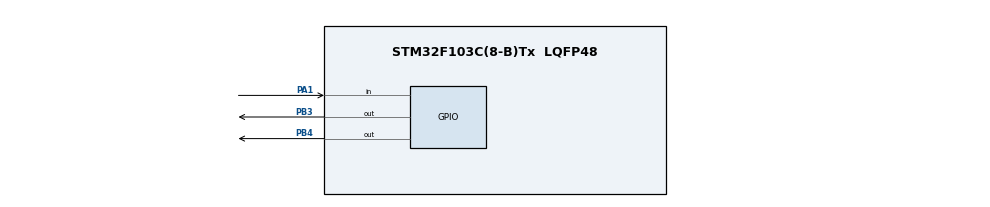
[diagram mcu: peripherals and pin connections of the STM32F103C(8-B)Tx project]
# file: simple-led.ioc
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Mcu.Family=STM32F1
Mcu.Name=STM32F103C(8-B)Tx
Mcu.Package=LQFP48
NVIC.PriorityGroup=NVIC_PRIORITYGROUP_4
PA1.Signal=GPIO_Input
PB3.Signal=GPIO_Output
PB4.Signal=GPIO_Output
ProjectManager.HeapSize=0x200
ProjectManager.StackSize=0x400
ProjectManager.TargetToolchain=STM32CubeIDE
RCC.APB1Freq_Value=8000000
RCC.APB2Freq_Value=8000000
VP_SYS_VS_ND.Mode=No_Debug
board=custom

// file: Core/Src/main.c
/* USER CODE BEGIN Header */
/**
  ******************************************************************************
  * @file           : main.c
  * @brief          : Main program body
  ******************************************************************************
  * @attention
  *
  * Copyright (c) 2023 STMicroelectronics.
  * All rights reserved.
  *
  * This software is licensed under terms that can be found in the LICENSE file
  * in the root directory of this software component.
  * If no LICENSE file comes with this software, it is provided AS-IS.
  *
  ******************************************************************************
  */
/* USER CODE END Header */
#include "main.h"
#include "led.h"
#include "key.h"

LED_TOGGLE(5, GPIOB, GPIO_PIN_5)

LED_TOGGLE(6, GPIOB, GPIO_PIN_6)

void SystemClock_Config(void);
static void MX_GPIO_Init(void);

int main(void)
{

  /* MCU Configuration--------------------------------------------------------*/

  /* Reset of all peripherals, Initializes the Flash interface and the Systick. */
  HAL_Init();

  /* Configure the system clock */
  SystemClock_Config();

  /* Initialize all configured peripherals */
  MX_GPIO_Init();

  /* Infinite loop */
  /* USER CODE BEGIN WHILE */
    int state = 0;
    while (1) {
    /* USER CODE END WHILE */
        int pressed_key = scan_key();
        if (pressed_key & 0x1) {
            state = (state + 1) % 2;
        }
        HAL_Delay(100);
        if (state == 1) {
            led_off(GPIOB, GPIO_PIN_5);
            toggle_6();
        } else {
            led_off(GPIOB, GPIO_PIN_6);
            toggle_5();
        }

    }
}

void SystemClock_Config(void)
{
  RCC_OscInitTypeDef RCC_OscInitStruct = {0};
  RCC_ClkInitTypeDef RCC_ClkInitStruct = {0};

  /** Initializes the RCC Oscillators according to the specified parameters
  * in the RCC_OscInitTypeDef structure.
  */
  RCC_OscInitStruct.OscillatorType = RCC_OSCILLATORTYPE_HSI;
  RCC_OscInitStruct.HSIState = RCC_HSI_ON;
  RCC_OscInitStruct.HSICalibrationValue = RCC_HSICALIBRATION_DEFAULT;
  RCC_OscInitStruct.PLL.PLLState = RCC_PLL_NONE;
  if (HAL_RCC_OscConfig(&RCC_OscInitStruct) != HAL_OK)
  {
    Error_Handler();
  }

  /** Initializes the CPU, AHB and APB buses clocks
  */
  RCC_ClkInitStruct.ClockType = RCC_CLOCKTYPE_HCLK|RCC_CLOCKTYPE_SYSCLK
                              |RCC_CLOCKTYPE_PCLK1|RCC_CLOCKTYPE_PCLK2;
  RCC_ClkInitStruct.SYSCLKSource = RCC_SYSCLKSOURCE_HSI;
  RCC_ClkInitStruct.AHBCLKDivider = RCC_SYSCLK_DIV1;
  RCC_ClkInitStruct.APB1CLKDivider = RCC_HCLK_DIV1;
  RCC_ClkInitStruct.APB2CLKDivider = RCC_HCLK_DIV1;

  if (HAL_RCC_ClockConfig(&RCC_ClkInitStruct, FLASH_LATENCY_0) != HAL_OK)
  {
    Error_Handler();
  }
}

static void MX_GPIO_Init(void)
{
  GPIO_InitTypeDef GPIO_InitStruct = {0};

  /* GPIO Ports Clock Enable */
  __HAL_RCC_GPIOA_CLK_ENABLE();
  __HAL_RCC_GPIOB_CLK_ENABLE();

  /*Configure GPIO pin Output Level */
  HAL_GPIO_WritePin(GPIOB, GPIO_PIN_5|GPIO_PIN_6, GPIO_PIN_RESET);

  /*Configure GPIO pin : PA1 */
  GPIO_InitStruct.Pin = GPIO_PIN_1;
  GPIO_InitStruct.Mode = GPIO_MODE_INPUT;
  GPIO_InitStruct.Pull = GPIO_PULLDOWN;
  HAL_GPIO_Init(GPIOA, &GPIO_InitStruct);

  /*Configure GPIO pins : PB5 PB6 */
  GPIO_InitStruct.Pin = GPIO_PIN_5|GPIO_PIN_6;
  GPIO_InitStruct.Mode = GPIO_MODE_OUTPUT_PP;
  GPIO_InitStruct.Pull = GPIO_NOPULL;
  GPIO_InitStruct.Speed = GPIO_SPEED_FREQ_LOW;
  HAL_GPIO_Init(GPIOB, &GPIO_InitStruct);

}

void Error_Handler(void)
{
    __disable_irq();
    while (1) {
    }
}
